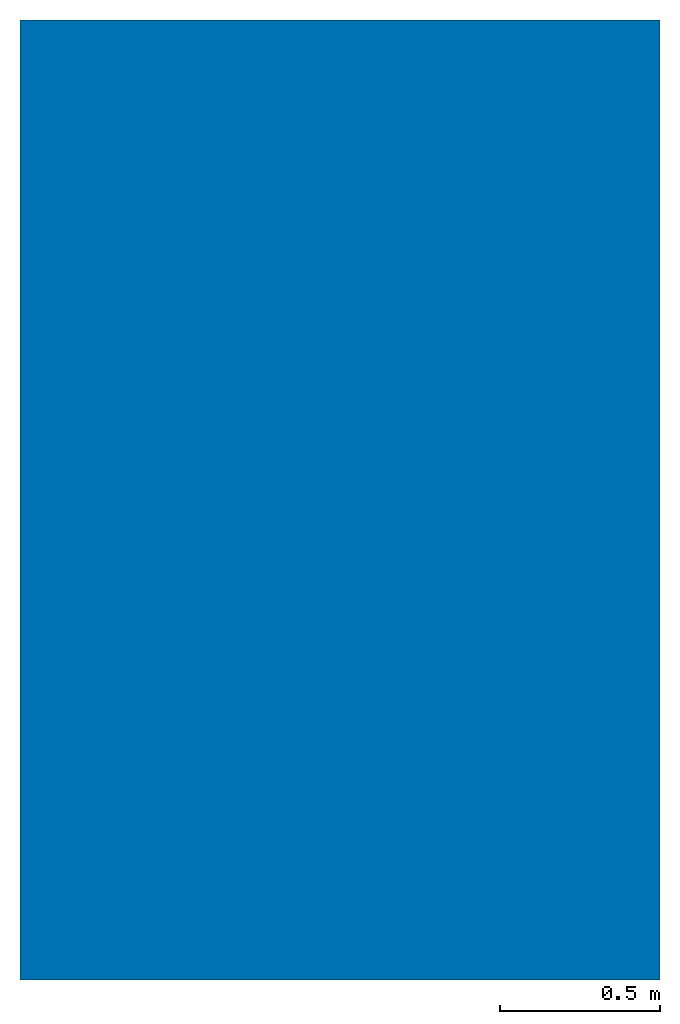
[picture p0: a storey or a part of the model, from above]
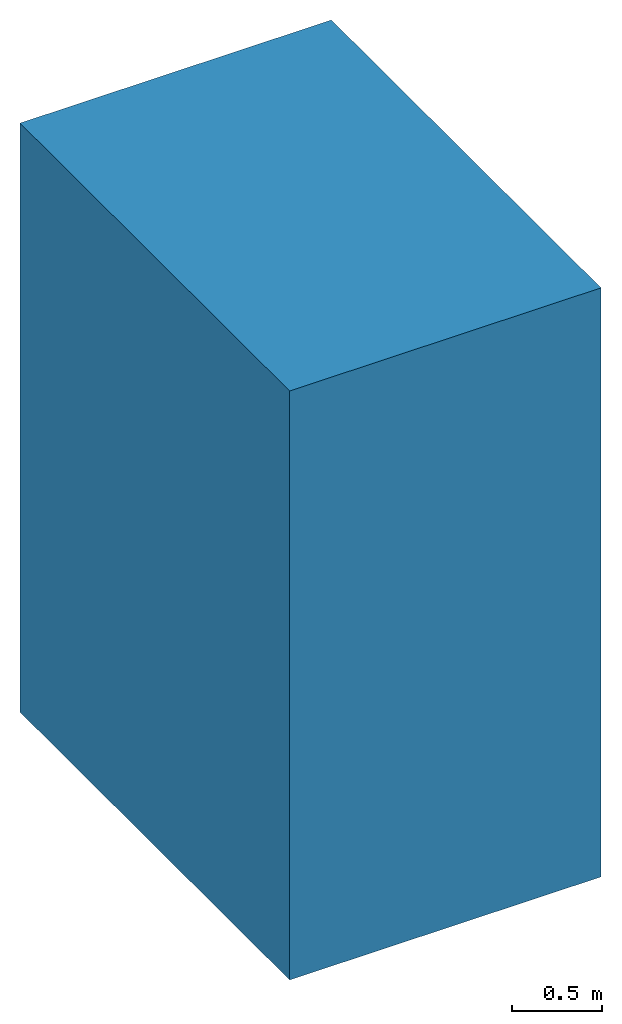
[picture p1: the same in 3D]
Properties of the parts of a building model (IFC4)

# File
File name: José's Project
Author: IngeTrazo
Organization: IngeTrazo
Written by: IngeTrazo Rust
Made in: IngeTrazo

# IfcBuildingStorey, Storey 1
In: Building 1
Elevation: 0 m

# IfcWall, Muro de José IfcWall
In: Storey 1
Qto_WallBaseQuantities - Height: 4 m; Length: 3 m; Width: 2 m; GrossSideArea: 12 m2; NetSideArea: 12 m2; GrossVolume: 24 m3
